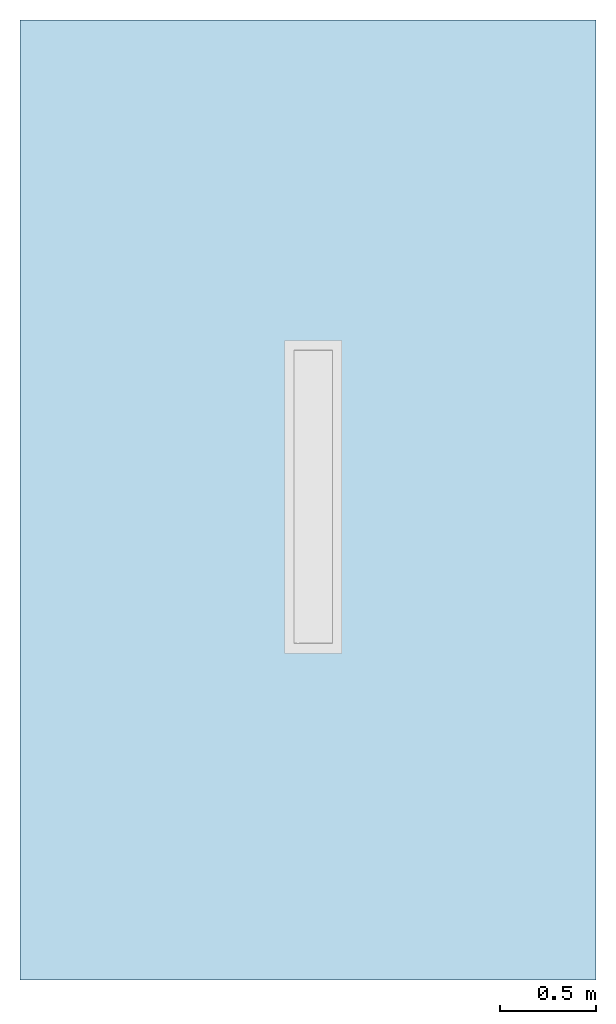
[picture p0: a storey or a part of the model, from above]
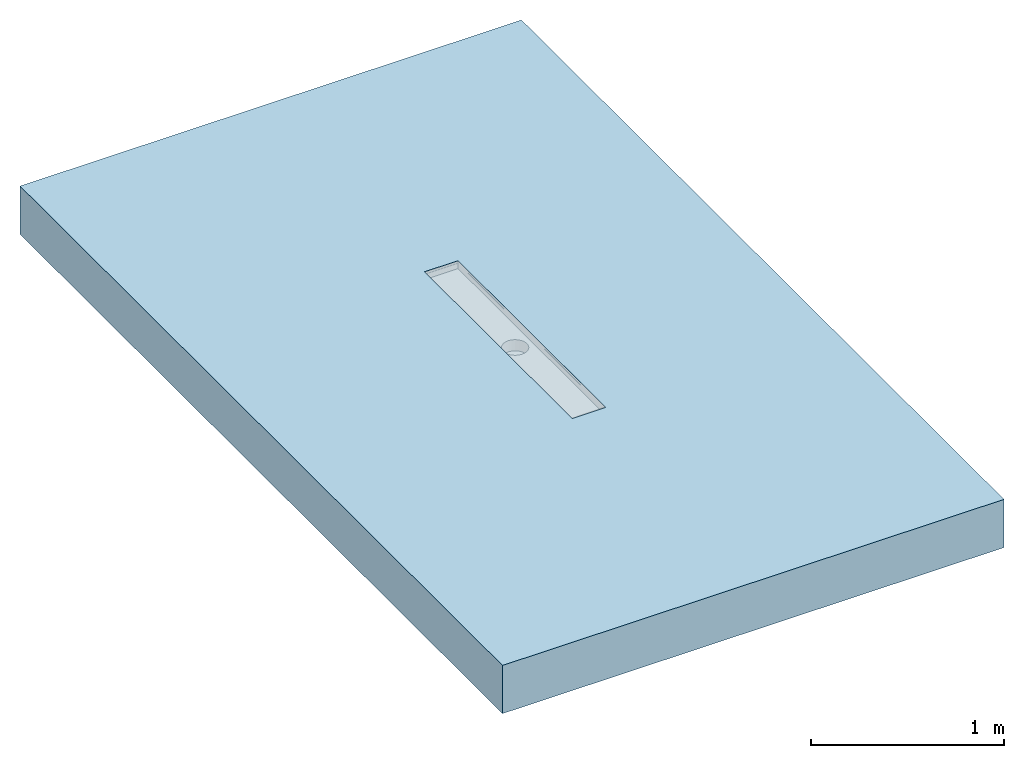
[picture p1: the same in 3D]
Properties of the parts of a building model (IFC2X3)

# File
Description: ViewDefinition [CoordinationView]
File name: Project Number
Time: 2016-11-22T09:06:33
Written by: The EXPRESS Data Manager Version 5.01.0100.02.64mod : 6 Jun 2012
Made in: 20130308_1515(x64) - Exporter 2014.0.2013.0308 - Default UI
Comment: STEP Physical File produced by: The EXPRESS Data Manager Version 5.01.0100.02.64mod : 6 Jun 2012 * Module: EDMstepFileFactory/EDMstandAlone * Creation date: Tue Nov 22 09:06:33 2016 * Host: IN-BLR-PC-0012 * Database: C:\Users\pakumar\AppData\Local\Temp\{A1B2DFF3-C551-4D06-8A07-789360830C3E}\ifc * Database version: 5507 * Database creation date: Tue Nov 22 09:06:32 2016 * Schema: IFC2X3 * Model: DataRepository.ifc * Model creation date: Tue Nov 22 09:06:32 2016 * Header model: DataRepository.ifc_HeaderModel * Header model creation date: Tue Nov 22 09:06:32 2016 * EDMuser: sdai-user * EDMgroup: sdai-group * License ID and type: 5605 : Permanent license. Expiry date: * EDMstepFileFactory options: 020000

# IfcProject, Project Number
LongName: Project Name; Phase: Project Status

# IfcSite, Default
RefLatitude: 42, 21, 30, 344238; RefLongitude: -71, -3, -35, -194702; RefElevation: 0 mm

# IfcBuilding
Pset_BuildingCommon - NumberOfStoreys: 1
Other - Project Issue Date: Issue Date; Project Status: Project Status; Client Name: Owner; Project Number: Project Number; Project Address: Enter address here; Project Name: Project Name

# IfcBuildingStorey, Level 1
LongName: Level 1; Elevation: 0 mm
Constraints - Elevation Base: Project Base Point; Elevation: 0 mm
Graphics - Symbol at End 1 Default: no; Color: 0; Symbol: Level Head - Circle: Level Head - Circle; Symbol at End 2 Default: yes; Line Pattern: Grid Line 1/2"; Line Weight: 1
Identity Data - Structural: no; Name: Level 1; Building Story: yes
Dimensions - Computation Height: 0 mm

# IfcFlowTerminal: 416690 - Hygienic Extended Channel - with Gully 157 - 1500mm LG - 200mm Wide, ACO Tray Channel - Hygienic - Extended - 200mm Wide:416690 - Hygienic Extended Channel - with Gully 157 - 1500mm LG - 200mm Wide:224960
In: Level 1
Material: Stainless Steel AISI 304, Stainless Steel AISI 304 - Grating
Construction - Detail - Outlet 125mm: no; Detail - Outlet 110mm: no; Detail - Outlet 142mm: yes; Grating: yes; 416810 - 168 x 398mm - Ladder Grating - M125 - Stainless steel 1.4301: no; 416947 - 168 x 499mm - Casted Grating - M125 - Stainless steel 1.4301: yes; 416860 - 168 x 499mm - Mesh Grating - L15 - Stainless steel 1.4301: no; 416882 - 168 x 398mm - Mesh Grating - L15 - Stainless steel 1.4301: no; 416948 - 168 x 399mm - Casted Grating - M125 - Stainless steel 1.4301: no; 416808 - 168 x 398mm - Ladder Grating - R50 - Stainless steel 1.4301: no; 416804 - 168 x 499mm - Ladder Grating - M125 - Stainless steel 1.4301: no; 416880 - 168 x 499mm - Mesh Grating - L15 - Stainless steel 1.4301: no; 416862 - 168 x 398mm - Mesh Grating - L15 - Stainless steel 1.4301: no; 416802 - 168 x 499mm - Ladder Grating - R50 - Stainless steel 1.4301: no
Phasing - Phase Created: New Construction
Mechanical - System Classification: Sanitary
Identity Data - Mark: 5; Telephone: +44 (0)1462 816666; Website: www.acobd.com; Manufacturer: ACO Building Drainage; E-mail Technical: abdtechnical@aco.co.uk; Watermark1: This file is the property of ACO Technologies PLC; Fax: +44 (0)1462 851490; E-mail Sales: abdcommercial@aco.co.uk; Cost: 0; Watermarked With: BIM Manager Premium Suite; Address: ACO Business Centre, Caxton Road, Bedford, MK41 0LF; Watermark2: This file is water marked and users are prohibited to reproduce, adapt, distribute this information; Watermarked By: www.acobd.com
Constraints - Level: Level: Level 1
Pset_ManufacturerTypeInformation - Manufacturer: ACO Building Drainage
General - Foul air trap seal Material: NBR; Product Range: ACO Hygiene First; Product Standard: EN 1253 / EN 1672 / EN ISO 14159; Foul air trap Recyclable: Fully recyclable; Load Class: A15 - C250 (EN 1253); Channel Dimension: 200 x 1530; Channel Recyclable: Fully recyclable; Foul air trap seal Colour: Black; Weight (Kg): 9.2; Channel Colour: passivated stainless steel surface ( matt grey); Product Type: Extended Kitchen Tray Channel; Maintenance guidelines: http://issuu.com/acobuildingdrainage/docs/aco_hygiene_first_catalogue/17?e=0; Channel Material: Stainless steel 1.4301 (EN 10088); Outlet Diameter (mm): 142; Installation guidelines: http://issuu.com/acobuildingdrainage/docs/aco_hygiene_first_catalogue/17?e=0; Foul air trap Recycled material content: 0%; Price: POA - contact ACO; Channel Recycled material content: 20 - 30 %; Product Code: 416690; Product Description: ACO Hygiene First Extended Kitchen Tray Channel 200 x 1530 / 142 Dia Outlet & Foul Air Trap
Model Properties - Grating Product Code 416948: N/A; Grating Product Code 416860: Load Class L 15 (EN 1253) - Mesh Grate - Stainless steel 1.4301 (EN 10088) - 168 x 499 - 2.2kg; Grating Product Code 416804: Load Class M 125 (EN 1253) - Ladder Grate - Stainless steel 1.4301 (EN 10088) - 168 x 499 - 4.4kg; Grating Product Code 416882: N/A; Grating Product Code 416947: Load Class M 125 (EN 1253) - Caste Grate - Stainless steel 1.4301 (EN 10088) - 168 x 499 - 6.4kg; Grating Product Code 416808: N/A; Grating Product Code 416802: Load Class R 50 (EN 1253) - Ladder Grate - Stainless steel 1.4301 (EN 10088) - 168 x 499 - 6.4kg; Grating Product Code 416862: N/A; Grating Product Code 416810: N/A; Grating Product Code 416880: Load Class L 15 (EN 1253) - Mesh Grate - Stainless steel 1.4301 (EN 10088) - 168 x 499 - 2.3kg
Other - Array: 61; Spigot Outlets Channels: yes; Length 800: no; Length 1500: yes; Length 500: no; Length 1000: no; Length 2000: no; Length 1200: no; Flow: 0.0988811 m3/s; Invert Depth Detail: 51.5 mm
Dimensions - Extention Length: -1565 mm; End Connection Plate End: -1500 mm; Length Channel: -1470 mm; Outside Outlet Rad: 71 mm; End Plate: 1500 mm; Inside Outlet Rad: 69 mm; End Connection Plate Start: -1470 mm; Outlet: 142 mm; Floor Cut Void Height: 62.8 mm; Number of gratings: 3; Grating Length: 499 mm; Endplate Position: 1500 mm; Depth: 29 mm; Invert Depth: 50 mm; Spigot Distance: 750 mm; Grating Height: 21 mm; x: -1515 mm; Grating Void Cut Length: 500 mm

# IfcOpeningElement: Recess
In: Level 1
Dimensions - Volume: 160.869 ft3; Perimeter: 16000 mm; Area: 161.459 ft2; Thickness: 304.8 mm
Constraints - Related to Mass: no; Room Bounding: yes; Height Offset From Level: 0 mm; Level: Level: Level 1
Phasing - Phase Created: New Construction
Structural - Enable Analytical Model: no; Structural: no
Identity Data - Assembly Code: B1010; Assembly Description: Floor Construction
Graphics - Coarse Scale Fill Color: 0
Construction - Default Thickness: 304.8 mm; Function: Interior
Analytical Properties - Absorptance: 0.7; Roughness: 3

# IfcSlab: Floor:Generic - 12", Floor:Generic - 12":184145
In: Level 1
PredefinedType: FLOOR; Material: Default Floor 304.8 mm
Dimensions - Volume: 160.869 ft3; Perimeter: 16000 mm; Area: 161.459 ft2; Thickness: 304.8 mm
Constraints - Related to Mass: no; Room Bounding: yes; Height Offset From Level: 0 mm; Level: Level: Level 1
Phasing - Phase Created: New Construction
Structural - Enable Analytical Model: no; Structural: no
Pset_SlabCommon - Reference: Generic - 12"; IsExternal: no; LoadBearing: yes
Identity Data - Assembly Code: B1010; Assembly Description: Floor Construction
Graphics - Coarse Scale Fill Color: 0
Construction - Default Thickness: 304.8 mm; Function: Interior
Analytical Properties - Absorptance: 0.7; Roughness: 3
